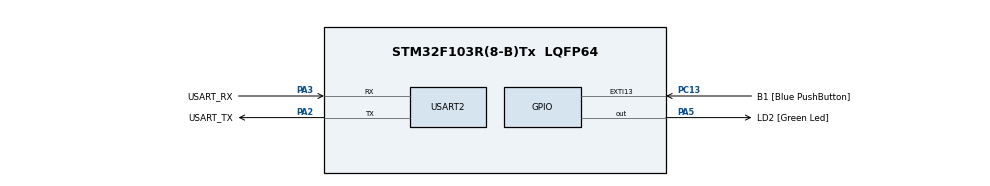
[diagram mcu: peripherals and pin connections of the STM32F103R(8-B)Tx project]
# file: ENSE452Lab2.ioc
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Mcu.Family=STM32F1
Mcu.Name=STM32F103R(8-B)Tx
Mcu.Package=LQFP64
NVIC.EXTI15_10_IRQn=true\:0\:0\:false\:false\:true\:true\:true\:true
NVIC.PriorityGroup=NVIC_PRIORITYGROUP_4
PA13.GPIO_Label=TMS
PA13.Mode=Serial_Wire
PA13.Signal=SYS_JTMS-SWDIO
PA14.GPIO_Label=TCK
PA14.Mode=Serial_Wire
PA14.Signal=SYS_JTCK-SWCLK
PA2.GPIO_Label=USART_TX
PA2.GPIO_Mode=GPIO_MODE_AF_PP
PA2.GPIO_PuPd=GPIO_NOPULL
PA2.GPIO_Speed=GPIO_SPEED_FREQ_LOW
PA2.Mode=Asynchronous
PA2.Signal=USART2_TX
PA3.GPIO_Label=USART_RX
PA3.GPIO_Mode=GPIO_MODE_AF_PP
PA3.GPIO_PuPd=GPIO_NOPULL
PA3.GPIO_Speed=GPIO_SPEED_FREQ_LOW
PA3.Mode=Asynchronous
PA3.Signal=USART2_RX
PA5.GPIO_Label=LD2 [Green Led]
PA5.GPIO_ModeDefaultOutputPP=GPIO_MODE_OUTPUT_PP
PA5.GPIO_PuPd=GPIO_NOPULL
PA5.GPIO_Speed=GPIO_SPEED_FREQ_LOW
PA5.Signal=GPIO_Output
PB3.GPIO_Label=SWO
PB3.Signal=SYS_JTDO-TRACESWO
PC13-TAMPER-RTC.GPIO_Label=B1 [Blue PushButton]
PC13-TAMPER-RTC.GPIO_PuPd=GPIO_NOPULL
PC13-TAMPER-RTC.Signal=GPXTI13
PC14-OSC32_IN.Mode=LSE-External-Oscillator
PC14-OSC32_IN.Signal=RCC_OSC32_IN
PC15-OSC32_OUT.Mode=LSE-External-Oscillator
PC15-OSC32_OUT.Signal=RCC_OSC32_OUT
PD0-OSC_IN.Mode=HSE-External-Clock-Source
PD0-OSC_IN.Signal=RCC_OSC_IN
PD1-OSC_OUT.Mode=HSE-External-Clock-Source
PD1-OSC_OUT.Signal=RCC_OSC_OUT
ProjectManager.HeapSize=0x200
ProjectManager.StackSize=0x400
ProjectManager.TargetToolchain=STM32CubeIDE
RCC.AHBFreq_Value=64000000
RCC.APB1CLKDivider=RCC_HCLK_DIV2
RCC.APB1Freq_Value=32000000
RCC.APB1TimFreq_Value=64000000
RCC.APB2Freq_Value=64000000
RCC.APB2TimFreq_Value=64000000
RCC.HCLKFreq_Value=64000000
RCC.PLLMUL=RCC_PLL_MUL16
RCC.RTCClockSelection=RCC_RTCCLKSOURCE_LSE
RCC.SYSCLKFreq_VALUE=64000000
RCC.SYSCLKSource=RCC_SYSCLKSOURCE_PLLCLK
RCC.USBFreq_Value=64000000
USART2.VirtualMode=VM_ASYNC
board=NUCLEO-F103RB

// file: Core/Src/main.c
/* USER CODE BEGIN Header
 *
 * Gregory Sveinbjornson
 * 200427591
 * Lab 2
 *
 * */

/**
  ******************************************************************************
  * @file           : main.c
  * @brief          : Main program body
  ******************************************************************************
  * @attention
  *
  * <h2><center>&copy; Copyright (c) 2020 STMicroelectronics.
  * All rights reserved.</center></h2>
  *
  * This software component is licensed by ST under BSD 3-Clause license,
  * the "License"; You may not use this file except in compliance with the
  * License. You may obtain a copy of the License at:
  *                        opensource.org/licenses/BSD-3-Clause
  *
  ******************************************************************************
  */
/* USER CODE END Header */
#include "main.h"

/* USER CODE BEGIN Includes */
#include <string.h>
/* USER CODE END Includes */

UART_HandleTypeDef huart2;

/* USER CODE BEGIN PV */
uint8_t cliBufferTX[50];
uint8_t cliBufferRX[10];
uint8_t input[15];
/* USER CODE END PV */

void SystemClock_Config(void);
static void MX_GPIO_Init(void);
static void MX_USART2_UART_Init(void);

int main(void)
{

  /* MCU Configuration--------------------------------------------------------*/

  /* Reset of all peripherals, Initializes the Flash interface and the Systick. */
  HAL_Init();

  /* Configure the system clock */
  SystemClock_Config();

  /* Initialize all configured peripherals */
  MX_GPIO_Init();
  MX_USART2_UART_Init();
  /* USER CODE BEGIN 2 */
  int x;
  /* USER CODE END 2 */

  /* Infinite loop */
  /* USER CODE BEGIN WHILE */

  while (1)
  {
	  x = 0;

	  strcpy((char *)cliBufferTX, "\nEnter a command for the LED:\r\n");
	  HAL_UART_Transmit(&huart2, cliBufferTX, strlen((char *)cliBufferTX), 1000);

	  while(cliBufferTX[0] != '\r')
	  {
		  if(HAL_UART_Receive(&huart2, cliBufferRX, 1, 300) == HAL_OK)
		  {
			  if(cliBufferRX[0] == '\b')
			  {
				  cliBufferTX[0] = cliBufferRX[0];
				  cliBufferTX[1] = ' ';
				  cliBufferTX[2] = '\b';
				  HAL_UART_Transmit(&huart2, cliBufferTX, 3, 1000);
				  x--;
			  }
			  else
			  {
				  cliBufferTX[0] = cliBufferRX[0];
				  input[x] = cliBufferRX[0];
				  HAL_UART_Transmit(&huart2, cliBufferTX, 1, 1000);
				  x++;
			  }
		  }
	  }

	  if(input[0] == 'h' && input[1] == 'e' && input[2] == 'l' && input[3] == 'p' && input[4] == '\r')
	  {
		  strcpy((char *)cliBufferTX, "\non -> turns the green LED on\r\n");
		  HAL_UART_Transmit(&huart2, cliBufferTX, strlen((char *)cliBufferTX), 1000);
		  strcpy((char *)cliBufferTX, "\noff -> turns the green LED off\r\n");
		  HAL_UART_Transmit(&huart2, cliBufferTX, strlen((char *)cliBufferTX), 1000);
		  strcpy((char *)cliBufferTX, "\nquery -> returns the state of the green LED\r\n");
		  HAL_UART_Transmit(&huart2, cliBufferTX, strlen((char *)cliBufferTX), 1000);
	  }
	  else if(input[0] == 'o' && input[1] == 'n' && input[2] == '\r')
	  {
		  if(HAL_GPIO_ReadPin(GPIOA, GPIO_PIN_5) == 1)
		  {
			  strcpy((char *)cliBufferTX, "\nThe LED is already on!\r\n");
		  }
		  else
		  {
			  strcpy((char *)cliBufferTX, "\nDone!\r\n");
		  }
		  HAL_UART_Transmit(&huart2, cliBufferTX, strlen((char *)cliBufferTX), 1000);
		  HAL_GPIO_WritePin(GPIOA, GPIO_PIN_5, GPIO_PIN_SET);

	  }
	  else if(input[0] == 'o' && input[1] == 'f' && input[2] == 'f' && input[3] == '\r')
	  {
		  if(HAL_GPIO_ReadPin(GPIOA, GPIO_PIN_5) == 1)
		  {
			  strcpy((char *)cliBufferTX, "\nDone!\r\n");
		  }
		  else
		  {
			  strcpy((char *)cliBufferTX, "\nThe LED is already off!\r\n");
		  }
		  HAL_UART_Transmit(&huart2, cliBufferTX, strlen((char *)cliBufferTX), 1000);
		  HAL_GPIO_WritePin(GPIOA, GPIO_PIN_5, GPIO_PIN_RESET);
	  }
	  else if(input[0] == 'q' && input[1] == 'u' && input[2] == 'e' && input[3] == 'r' && input[4] == 'y' && input[5] == '\r')
	  {
		  if(HAL_GPIO_ReadPin(GPIOA, GPIO_PIN_5) == 1)
		  {
			  strcpy((char *)cliBufferTX, "\nThe LED is on!\r\n");
		  }
		  else
		  {
			  strcpy((char *)cliBufferTX, "\nThe LED is off!\r\n");
		  }
		  HAL_UART_Transmit(&huart2, cliBufferTX, strlen((char *)cliBufferTX), 1000);
	  }
	  else if(input[0] == '\r')
	  {
		  continue;
	  }
	  else
	  {
		  strcpy((char *)cliBufferTX, "\nError. Try again.\r\n");
		  HAL_UART_Transmit(&huart2, cliBufferTX, strlen((char *)cliBufferTX), 1000);
	  }

    /* USER CODE END WHILE */

  }
}

void SystemClock_Config(void)
{
  RCC_OscInitTypeDef RCC_OscInitStruct = {0};
  RCC_ClkInitTypeDef RCC_ClkInitStruct = {0};

  /** Initializes the RCC Oscillators according to the specified parameters
  * in the RCC_OscInitTypeDef structure.
  */
  RCC_OscInitStruct.OscillatorType = RCC_OSCILLATORTYPE_HSI;
  RCC_OscInitStruct.HSIState = RCC_HSI_ON;
  RCC_OscInitStruct.HSICalibrationValue = RCC_HSICALIBRATION_DEFAULT;
  RCC_OscInitStruct.PLL.PLLState = RCC_PLL_NONE;
  if (HAL_RCC_OscConfig(&RCC_OscInitStruct) != HAL_OK)
  {
    Error_Handler();
  }
  /** Initializes the CPU, AHB and APB buses clocks
  */
  RCC_ClkInitStruct.ClockType = RCC_CLOCKTYPE_HCLK|RCC_CLOCKTYPE_SYSCLK
                              |RCC_CLOCKTYPE_PCLK1|RCC_CLOCKTYPE_PCLK2;
  RCC_ClkInitStruct.SYSCLKSource = RCC_SYSCLKSOURCE_HSI;
  RCC_ClkInitStruct.AHBCLKDivider = RCC_SYSCLK_DIV1;
  RCC_ClkInitStruct.APB1CLKDivider = RCC_HCLK_DIV1;
  RCC_ClkInitStruct.APB2CLKDivider = RCC_HCLK_DIV1;

  if (HAL_RCC_ClockConfig(&RCC_ClkInitStruct, FLASH_LATENCY_0) != HAL_OK)
  {
    Error_Handler();
  }
}

static void MX_USART2_UART_Init(void)
{

  huart2.Instance = USART2;
  huart2.Init.BaudRate = 115200;
  huart2.Init.WordLength = UART_WORDLENGTH_8B;
  huart2.Init.StopBits = UART_STOPBITS_1;
  huart2.Init.Parity = UART_PARITY_NONE;
  huart2.Init.Mode = UART_MODE_TX_RX;
  huart2.Init.HwFlowCtl = UART_HWCONTROL_NONE;
  huart2.Init.OverSampling = UART_OVERSAMPLING_16;
  if (HAL_UART_Init(&huart2) != HAL_OK)
  {
    Error_Handler();
  }

}

static void MX_GPIO_Init(void)
{
  GPIO_InitTypeDef GPIO_InitStruct = {0};

  /* GPIO Ports Clock Enable */
  __HAL_RCC_GPIOA_CLK_ENABLE();

  /*Configure GPIO pin Output Level */
  HAL_GPIO_WritePin(GPIOA, GPIO_PIN_5, GPIO_PIN_RESET);

  /*Configure GPIO pin : PA5 */
  GPIO_InitStruct.Pin = GPIO_PIN_5;
  GPIO_InitStruct.Mode = GPIO_MODE_OUTPUT_PP;
  GPIO_InitStruct.Pull = GPIO_NOPULL;
  GPIO_InitStruct.Speed = GPIO_SPEED_FREQ_LOW;
  HAL_GPIO_Init(GPIOA, &GPIO_InitStruct);

}

void Error_Handler(void)
{
}

/************************ (C) COPYRIGHT STMicroelectronics *****END OF FILE****/
